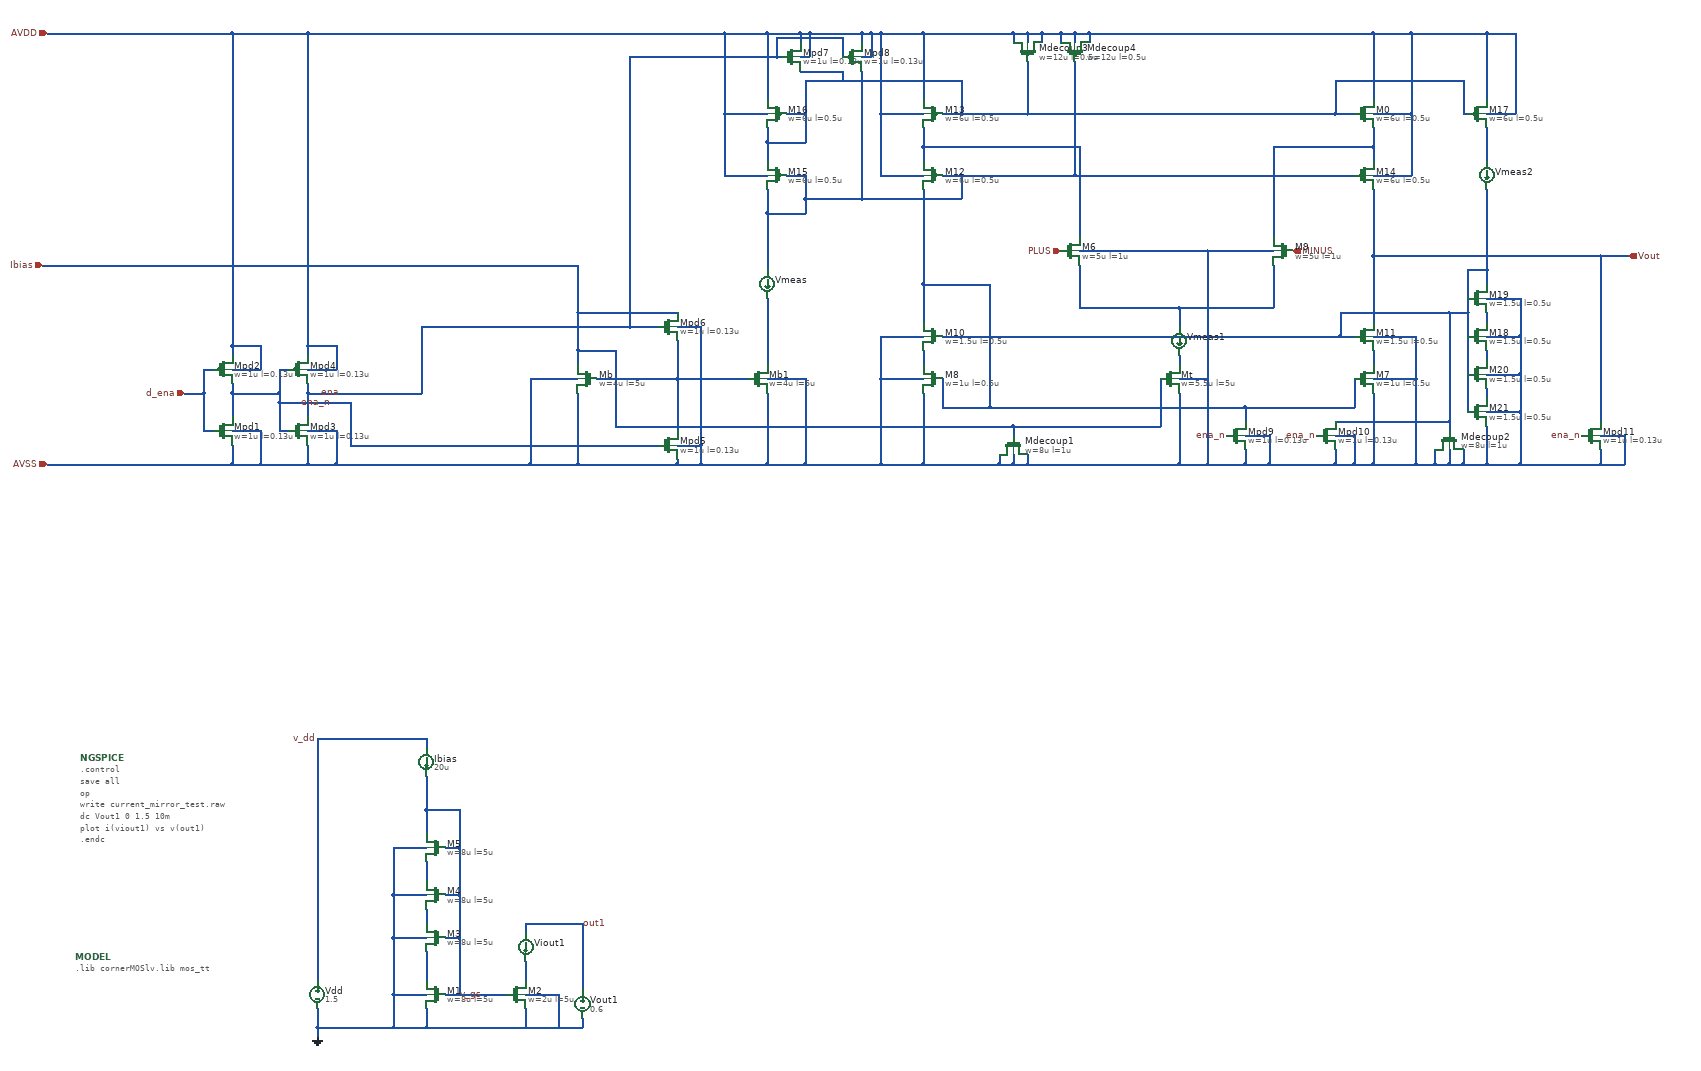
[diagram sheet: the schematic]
v {xschem version=3.4.6 file_version=1.2}
G {}
K {}
V {}
S {}
E {}
N 540 -170 540 -150 {
lab=GND}
N 700 -240 770 -240 {
lab=GND}
N 540 -780 770 -780 {
lab=v_dd}
N 810 -240 840 -240 {
lab=v_gs}
N 770 -780 770 -760 {
lab=v_dd}
N 770 -330 770 -270 {
lab=#net1}
N 980 -240 1050 -240 {
lab=GND}
N 540 -170 700 -170 {
lab=GND}
N 540 -210 540 -170 {
lab=GND}
N 700 -240 700 -170 {
lab=GND}
N 700 -170 770 -170 {
lab=GND}
N 770 -210 770 -170 {
lab=GND}
N 770 -170 980 -170 {
lab=GND}
N 980 -210 980 -170 {
lab=GND}
N 980 -170 1050 -170 {
lab=GND}
N 1050 -240 1050 -170 {
lab=GND}
N 1100 -190 1100 -170 {
lab=GND}
N 1050 -170 1100 -170 {
lab=GND}
N 840 -240 940 -240 {
lab=v_gs}
N 980 -390 1100 -390 {
lab=out1}
N 1100 -390 1100 -250 {
lab=out1}
N 980 -310 980 -270 {
lab=#net2}
N 980 -390 980 -370 {
lab=out1}
N 770 -630 770 -580 {lab=v_gs}
N 770 -520 770 -480 {lab=#net3}
N 770 -420 770 -390 {lab=#net4}
N 700 -360 700 -240 {lab=GND}
N 700 -550 770 -550 {lab=GND}
N 700 -450 770 -450 {lab=GND}
N 700 -550 700 -450 {lab=GND}
N 700 -360 770 -360 {lab=GND}
N 700 -450 700 -360 {lab=GND}
N 770 -630 840 -630 {lab=v_gs}
N 770 -700 770 -630 {lab=v_gs}
N 840 -360 840 -240 {lab=v_gs}
N 810 -360 840 -360 {lab=v_gs}
N 840 -450 840 -360 {lab=v_gs}
N 810 -450 840 -450 {lab=v_gs}
N 840 -550 840 -450 {lab=v_gs}
N 810 -550 840 -550 {lab=v_gs}
N 840 -630 840 -550 {lab=v_gs}
N 540 -780 540 -270 {lab=v_dd}
N 2150 -1780 2150 -1690 {lab=#net1}
N 2560 -1780 2560 -1690 {lab=#net1}
N 2360 -1690 2560 -1690 {lab=#net1}
N 2770 -1360 2860 -1360 {lab=AVSS}
N 2360 -1510 2360 -1360 {lab=AVSS}
N 2040 -1360 2360 -1360 {lab=AVSS}
N 2420 -1810 2560 -1810 {lab=AVSS}
N 2360 -1540 2420 -1540 {lab=AVSS}
N 2420 -1540 2420 -1360 {lab=AVSS}
N 2360 -1360 2420 -1360 {lab=AVSS}
N 2420 -1810 2420 -1540 {lab=AVSS}
N 2150 -1810 2420 -1810 {lab=AVSS}
N 1730 -1540 1820 -1540 {lab=AVSS}
N 1730 -1540 1730 -1360 {lab=AVSS}
N 2770 -1540 2860 -1540 {lab=AVSS}
N 2860 -1540 2860 -1360 {lab=AVSS}
N 2770 -1510 2770 -1360 {lab=AVSS}
N 2730 -1360 2770 -1360 {lab=AVSS}
N 1820 -1510 1820 -1360 {lab=AVSS}
N 1730 -1360 1820 -1360 {lab=AVSS}
N 1820 -1600 1820 -1570 {lab=#net2}
N 1730 -1630 1730 -1540 {lab=AVSS}
N 1730 -1630 1820 -1630 {lab=AVSS}
N 2770 -1600 2770 -1570 {lab=#net3}
N 1860 -1540 1860 -1480 {lab=#net4}
N 2730 -1540 2730 -1480 {lab=#net4}
N 1820 -1740 1820 -1660 {lab=#net4}
N 1820 -2030 1820 -2000 {lab=#net5}
N 2770 -2030 2770 -2000 {lab=#net6}
N 1820 -2270 1820 -2130 {lab=AVDD}
N 2170 -2270 2770 -2270 {lab=AVDD}
N 2770 -2270 2770 -2130 {lab=AVDD}
N 1730 -2100 1820 -2100 {lab=AVDD}
N 1730 -2270 1730 -2100 {lab=AVDD}
N 1730 -2270 1820 -2270 {lab=AVDD}
N 2770 -2100 2850 -2100 {lab=AVDD}
N 2850 -2270 2850 -2100 {lab=AVDD}
N 2770 -2270 2850 -2270 {lab=AVDD}
N 1730 -1970 1820 -1970 {lab=AVDD}
N 1730 -2100 1730 -1970 {lab=AVDD}
N 2770 -1970 2850 -1970 {lab=AVDD}
N 2850 -2100 2850 -1970 {lab=AVDD}
N 2770 -1800 2770 -1660 {lab=Vout}
N 2770 -1630 2860 -1630 {lab=AVSS}
N 2860 -1630 2860 -1540 {lab=AVSS}
N 2560 -2030 2560 -1840 {lab=#net6}
N 2560 -2030 2770 -2030 {lab=#net6}
N 2770 -2070 2770 -2030 {lab=#net6}
N 2150 -2030 2150 -1840 {lab=#net5}
N 1820 -2030 2150 -2030 {lab=#net5}
N 1820 -2070 1820 -2030 {lab=#net5}
N 1820 -1740 1960 -1740 {lab=#net4}
N 1820 -1940 1820 -1740 {lab=#net4}
N 1960 -1740 1960 -1480 {lab=#net4}
N 1860 -1480 1960 -1480 {lab=#net4}
N 2690 -2100 2730 -2100 {lab=#net7}
N 2140 -1970 2730 -1970 {lab=#net8}
N 2500 -1480 2730 -1480 {lab=#net4}
N 3250 -1800 3310 -1800 {lab=Vout}
N 2770 -1940 2770 -1800 {lab=Vout}
N 1090 -1600 1090 -1570 {lab=Ibias}
N 2320 -1540 2320 -1440 {lab=Ibias}
N 990 -1360 1090 -1360 {lab=AVSS}
N 2010 -1440 2320 -1440 {lab=Ibias}
N 1090 -1510 1090 -1360 {lab=AVSS}
N 990 -1540 1090 -1540 {lab=AVSS}
N 990 -1540 990 -1360 {lab=AVSS}
N 1090 -1600 1170 -1600 {lab=Ibias}
N 1090 -1680 1090 -1600 {lab=Ibias}
N 1170 -1600 1170 -1540 {lab=Ibias}
N 1130 -1540 1170 -1540 {lab=Ibias}
N 1170 -1540 1170 -1440 {lab=Ibias}
N 1490 -2040 1490 -2000 {lab=#net7}
N 1490 -2270 1490 -2130 {lab=AVDD}
N 1400 -2270 1490 -2270 {lab=AVDD}
N 1400 -1970 1490 -1970 {lab=AVDD}
N 1400 -2100 1400 -1970 {lab=AVDD}
N 1400 -2100 1490 -2100 {lab=AVDD}
N 1490 -2040 1570 -2040 {lab=#net7}
N 1490 -2070 1490 -2040 {lab=#net7}
N 1570 -2100 1570 -2040 {lab=#net7}
N 1530 -2100 1570 -2100 {lab=#net7}
N 1570 -1920 1570 -1890 {lab=#net8}
N 1530 -1970 1570 -1970 {lab=#net8}
N 1490 -1890 1570 -1890 {lab=#net8}
N 1490 -1940 1490 -1890 {lab=#net8}
N 1570 -1360 1730 -1360 {lab=AVSS}
N 2700 -1630 2730 -1630 {lab=#net9}
N 1900 -2170 1900 -2100 {lab=#net7}
N 1860 -2100 1900 -2100 {lab=#net7}
N 1900 -1970 1900 -1920 {lab=#net8}
N 1860 -1970 1900 -1970 {lab=#net8}
N 1710 -2270 1730 -2270 {lab=AVDD}
N 2690 -2170 2690 -2100 {lab=#net7}
N 2040 -2100 2690 -2100 {lab=#net7}
N 2690 -2170 2960 -2170 {lab=#net7}
N 2960 -2170 2960 -2100 {lab=#net7}
N 2960 -2100 2970 -2100 {lab=#net7}
N 3010 -2270 3010 -2130 {lab=AVDD}
N 2850 -2270 3010 -2270 {lab=AVDD}
N 3010 -2100 3070 -2100 {lab=AVDD}
N 3070 -2270 3070 -2100 {lab=AVDD}
N 3010 -2270 3070 -2270 {lab=AVDD}
N 3010 -1630 3080 -1630 {lab=AVSS}
N 3080 -1470 3080 -1360 {lab=AVSS}
N 3010 -1360 3080 -1360 {lab=AVSS}
N 2700 -1680 2700 -1630 {lab=#net9}
N 1860 -1630 2700 -1630 {lab=#net9}
N 1490 -1510 1490 -1360 {lab=AVSS}
N 1350 -1360 1490 -1360 {lab=AVSS}
N 1490 -1540 1570 -1540 {lab=AVSS}
N 1570 -1540 1570 -1360 {lab=AVSS}
N 1490 -1360 1570 -1360 {lab=AVSS}
N 1300 -1540 1450 -1540 {lab=Ibias}
N 2970 -1680 2970 -1470 {lab=#net9}
N 2930 -1680 2970 -1680 {lab=#net9}
N 1400 -2270 1400 -2100 {lab=AVDD}
N 1690 -1920 1900 -1920 {lab=#net8}
N 1570 -1970 1570 -1920 {lab=#net8}
N 1570 -2170 1570 -2100 {lab=#net7}
N 1650 -2170 1900 -2170 {lab=#net7}
N 1490 -1890 1490 -1770 {lab=#net8}
N 1490 -1710 1490 -1570 {lab=#net10}
N 2360 -1690 2360 -1650 {lab=#net1}
N 2150 -1690 2360 -1690 {lab=#net1}
N 2360 -1590 2360 -1570 {lab=#net11}
N 3010 -2070 3010 -2000 {lab=#net12}
N 3010 -1770 3010 -1740 {lab=#net9}
N 2010 -1440 2010 -1420 {lab=Ibias}
N 1170 -1440 2010 -1440 {lab=Ibias}
N 2010 -1380 2010 -1360 {lab=AVSS}
N 1980 -1360 2010 -1360 {lab=AVSS}
N 2040 -1380 2040 -1360 {lab=AVSS}
N 2010 -1360 2040 -1360 {lab=AVSS}
N 1980 -1380 1980 -1360 {lab=AVSS}
N 1820 -1360 1980 -1360 {lab=AVSS}
N 2930 -1450 2930 -1430 {lab=#net9}
N 2700 -1680 2930 -1680 {lab=#net9}
N 2960 -1390 2960 -1360 {lab=AVSS}
N 2930 -1360 2960 -1360 {lab=AVSS}
N 2930 -1390 2930 -1360 {lab=AVSS}
N 2900 -1360 2930 -1360 {lab=AVSS}
N 2900 -1390 2900 -1360 {lab=AVSS}
N 2860 -1360 2900 -1360 {lab=AVSS}
N 2010 -2270 2010 -2250 {lab=AVDD}
N 1820 -2270 2010 -2270 {lab=AVDD}
N 2040 -2270 2040 -2250 {lab=AVDD}
N 2010 -2270 2040 -2270 {lab=AVDD}
N 2070 -2270 2070 -2250 {lab=AVDD}
N 2040 -2270 2070 -2270 {lab=AVDD}
N 2110 -2270 2110 -2250 {lab=AVDD}
N 2070 -2270 2110 -2270 {lab=AVDD}
N 2140 -2270 2140 -2250 {lab=AVDD}
N 2110 -2270 2140 -2270 {lab=AVDD}
N 2170 -2270 2170 -2250 {lab=AVDD}
N 2140 -2270 2170 -2270 {lab=AVDD}
N 2040 -2210 2040 -2100 {lab=#net7}
N 1900 -2100 2040 -2100 {lab=#net7}
N 2140 -2210 2140 -1970 {lab=#net8}
N 1900 -1970 2140 -1970 {lab=#net8}
N 520 -1400 520 -1360 {
lab=AVSS}
N 460 -1430 480 -1430 {
lab=ena_n}
N 520 -1430 580 -1430 {
lab=AVSS}
N 580 -1430 580 -1360 {
lab=AVSS}
N 460 -1560 480 -1560 {
lab=ena_n}
N 520 -1610 520 -1590 {
lab=AVDD}
N 520 -1560 580 -1560 {
lab=AVDD}
N 580 -1610 580 -1560 {
lab=AVDD}
N 520 -1610 580 -1610 {
lab=AVDD}
N 520 -1510 520 -1460 {
lab=ena}
N 360 -1400 360 -1360 {
lab=AVSS}
N 300 -1430 320 -1430 {
lab=d_ena}
N 360 -1430 420 -1430 {
lab=AVSS}
N 420 -1430 420 -1360 {
lab=AVSS}
N 300 -1560 320 -1560 {
lab=d_ena}
N 360 -1610 360 -1590 {
lab=AVDD}
N 360 -1560 420 -1560 {
lab=AVDD}
N 420 -1610 420 -1560 {
lab=AVDD}
N 360 -1610 420 -1610 {
lab=AVDD}
N 260 -1510 300 -1510 {
lab=d_ena}
N 300 -1510 300 -1430 {
lab=d_ena}
N 360 -1510 460 -1510 {
lab=ena_n}
N 360 -1510 360 -1460 {
lab=ena_n}
N 360 -1530 360 -1510 {
lab=ena_n}
N 460 -1560 460 -1510 {
lab=ena_n}
N 300 -1560 300 -1510 {
lab=d_ena}
N 460 -1490 460 -1430 {
lab=ena_n}
N 520 -1510 760 -1510 {
lab=ena}
N 520 -1530 520 -1510 {
lab=ena}
N 580 -1360 990 -1360 {lab=AVSS}
N -30 -1360 360 -1360 {lab=AVSS}
N 360 -1360 420 -1360 {lab=AVSS}
N 420 -1360 520 -1360 {lab=AVSS}
N 520 -1360 580 -1360 {lab=AVSS}
N 520 -2270 1400 -2270 {lab=AVDD}
N 360 -2270 360 -1610 {lab=AVDD}
N -30 -2270 360 -2270 {lab=AVDD}
N 460 -1490 610 -1490 {lab=ena_n}
N 460 -1510 460 -1490 {
lab=ena_n}
N 520 -2270 520 -1610 {lab=AVDD}
N 360 -2270 520 -2270 {lab=AVDD}
N 1300 -1650 1350 -1650 {lab=AVSS}
N 1350 -1400 1350 -1360 {lab=AVSS}
N 1300 -1360 1350 -1360 {lab=AVSS}
N 1300 -1400 1350 -1400 {lab=AVSS}
N 1350 -1650 1350 -1400 {lab=AVSS}
N 1300 -1370 1300 -1360 {lab=AVSS}
N 1090 -1360 1300 -1360 {lab=AVSS}
N 610 -1490 610 -1400 {lab=ena_n}
N 610 -1400 1260 -1400 {lab=ena_n}
N 1300 -1540 1300 -1430 {lab=Ibias}
N 1170 -1540 1300 -1540 {lab=Ibias}
N 1090 -1680 1300 -1680 {lab=Ibias}
N 1090 -1780 1090 -1680 {lab=Ibias}
N 760 -1650 760 -1510 {lab=ena}
N 1200 -1650 1260 -1650 {lab=ena}
N 1300 -1620 1300 -1540 {lab=Ibias}
N 1200 -2220 1200 -1650 {lab=ena}
N 760 -1650 1200 -1650 {lab=ena}
N 1510 -2220 1520 -2220 {lab=ena}
N 1560 -2270 1560 -2250 {lab=AVDD}
N 1490 -2270 1560 -2270 {lab=AVDD}
N 1560 -2220 1580 -2220 {lab=AVDD}
N 1580 -2270 1580 -2220 {lab=AVDD}
N 1560 -2270 1580 -2270 {lab=AVDD}
N 1560 -2190 1650 -2190 {lab=#net7}
N 1650 -2190 1650 -2170 {lab=#net7}
N 1570 -2170 1650 -2170 {lab=#net7}
N 1690 -2190 1690 -1920 {lab=#net8}
N 1570 -1920 1690 -1920 {lab=#net8}
N 1690 -2270 1690 -2250 {lab=AVDD}
N 1580 -2270 1690 -2270 {lab=AVDD}
N 1690 -2220 1710 -2220 {lab=AVDD}
N 1710 -2270 1710 -2220 {lab=AVDD}
N 1690 -2270 1710 -2270 {lab=AVDD}
N 1650 -2260 1650 -2220 {lab=ena}
N 1510 -2260 1650 -2260 {lab=ena}
N 1510 -2260 1510 -2220 {lab=ena}
N 1200 -2220 1510 -2220 {lab=ena}
N 2500 -1420 2550 -1420 {lab=AVSS}
N 2550 -1420 2550 -1360 {lab=AVSS}
N 2500 -1360 2550 -1360 {lab=AVSS}
N 2500 -1390 2500 -1360 {lab=AVSS}
N 2420 -1360 2500 -1360 {lab=AVSS}
N 2690 -1390 2690 -1360 {lab=AVSS}
N 2550 -1360 2690 -1360 {lab=AVSS}
N 2690 -1420 2730 -1420 {lab=AVSS}
N 2730 -1420 2730 -1360 {lab=AVSS}
N 2690 -1360 2730 -1360 {lab=AVSS}
N 2500 -1480 2500 -1450 {lab=#net4}
N 1960 -1480 2500 -1480 {lab=#net4}
N 2690 -1450 2930 -1450 {lab=#net9}
N 2930 -1680 2930 -1450 {lab=#net9}
N 3250 -1800 3250 -1450 {lab=Vout}
N 2770 -1800 3250 -1800 {lab=Vout}
N 3250 -1390 3250 -1360 {lab=AVSS}
N 3080 -1360 3250 -1360 {lab=AVSS}
N 3250 -1420 3300 -1420 {lab=AVSS}
N 3300 -1420 3300 -1360 {lab=AVSS}
N 3250 -1360 3300 -1360 {lab=AVSS}
N -40 -1780 1090 -1780 {lab=Ibias}
N 3010 -1680 3010 -1660 {lab=#net13}
N 3010 -1600 3010 -1580 {lab=#net14}
N 3010 -1520 3010 -1500 {lab=#net15}
N 3010 -1440 3010 -1360 {lab=AVSS}
N 2960 -1360 3010 -1360 {lab=AVSS}
N 3010 -1710 3080 -1710 {lab=AVSS}
N 3080 -1710 3080 -1630 {lab=AVSS}
N 3010 -1550 3080 -1550 {lab=AVSS}
N 3080 -1630 3080 -1550 {lab=AVSS}
N 3010 -1470 3080 -1470 {lab=AVSS}
N 3080 -1550 3080 -1470 {lab=AVSS}
N 2970 -1770 2970 -1680 {lab=#net9}
N 2970 -1770 3010 -1770 {lab=#net9}
N 3010 -1940 3010 -1770 {lab=#net9}
C {devices/vsource.sym} 540 -240 0 0 {name=Vdd value=1.5}
C {devices/gnd.sym} 540 -150 0 0 {name=l3 lab=GND}
C {sg13g2_pr/sg13_lv_nmos.sym} 790 -240 0 1 {name=M1
l=5u
w=8u
ng=1
m=1
model=sg13_lv_nmos
spiceprefix=X
}
C {devices/isource.sym} 770 -730 0 0 {name=Ibias value=20u}
C {devices/lab_pin.sym} 840 -240 0 1 {name=p1 sig_type=std_logic lab=v_gs}
C {devices/lab_pin.sym} 540 -780 0 0 {name=p2 sig_type=std_logic lab=v_dd}
C {sg13g2_pr/sg13_lv_nmos.sym} 960 -240 0 0 {name=M2
l=5u
w=2u
ng=1
m=1
model=sg13_lv_nmos
spiceprefix=X
}
C {devices/vsource.sym} 1100 -220 0 0 {name=Vout1 value=0.6
}
C {devices/spice_probe.sym} 980 -390 0 0 {name=p3 attrs=""}
C {devices/spice_probe.sym} 840 -290 0 0 {name=p6 attrs=""}
C {devices/lab_pin.sym} 1100 -390 0 1 {name=p7 sig_type=std_logic lab=out1}
C {devices/ammeter.sym} 980 -340 0 0 {name=Viout1 savecurrent=true spice_ignore=0}
C {sg13g2_pr/sg13_lv_nmos.sym} 790 -360 0 1 {name=M3
l=5u
w=8u
ng=1
m=1
model=sg13_lv_nmos
spiceprefix=X
}
C {sg13g2_pr/sg13_lv_nmos.sym} 790 -450 0 1 {name=M4
l=5u
w=8u
ng=1
m=1
model=sg13_lv_nmos
spiceprefix=X
}
C {sg13g2_pr/sg13_lv_nmos.sym} 790 -550 0 1 {name=M5
l=5u
w=8u
ng=1
m=1
model=sg13_lv_nmos
spiceprefix=X
}
C {devices/code_shown.sym} 40 -740 0 0 {name=NGSPICE only_toplevel=true 
value="

.control
save all

op
write current_mirror_test.raw
dc Vout1 0 1.5 10m
plot i(viout1) vs v(out1)


.endc
"}
C {devices/code_shown.sym} 30 -320 0 0 {name=MODEL only_toplevel=true
format="tcleval( @value )"
value=".lib cornerMOSlv.lib mos_tt
"}
C {devices/title.sym} 190 80 0 0 {name=l5 author="(c) 2025 Thesis_HP, Apache-2.0 license"}
C {ipin.sym} 2110 -1810 0 0 {name=p4 lab=PLUS}
C {ipin.sym} 2600 -1810 0 1 {name=p5 lab=MINUS
}
C {opin.sym} 3310 -1800 0 0 {name=p8 lab=Vout}
C {ipin.sym} -30 -2270 0 0 {name=p9 lab=AVDD}
C {sg13g2_pr/sg13_lv_nmos.sym} 2130 -1810 0 0 {name=M6
l=1u
w=5u
ng=1
m=1
model=sg13_lv_nmos
spiceprefix=X
}
C {sg13g2_pr/sg13_lv_nmos.sym} 2340 -1540 0 0 {name=Mt
l=5u
w=5.5u
ng=3
m=1
model=sg13_lv_nmos
spiceprefix=X
}
C {ipin.sym} -30 -1360 0 0 {name=p10 lab=AVSS}
C {sg13g2_pr/sg13_lv_nmos.sym} 2750 -1540 0 0 {name=M7
l=0.5u
w=1u
ng=1
m=1
model=sg13_lv_nmos
spiceprefix=X
}
C {sg13g2_pr/sg13_lv_nmos.sym} 1840 -1540 0 1 {name=M8
l=0.5u
w=1u
ng=1
m=1
model=sg13_lv_nmos
spiceprefix=X
}
C {sg13g2_pr/sg13_lv_nmos.sym} 2580 -1810 0 1 {name=M9
l=1u
w=5u
ng=1
m=1
model=sg13_lv_nmos
spiceprefix=X
}
C {sg13g2_pr/sg13_lv_nmos.sym} 1840 -1630 0 1 {name=M10
l=0.5u
w=1.5u
ng=1
m=1
model=sg13_lv_nmos
spiceprefix=X
}
C {sg13g2_pr/sg13_lv_nmos.sym} 2750 -1630 0 0 {name=M11
l=0.5u
w=1.5u
ng=1
m=1
model=sg13_lv_nmos
spiceprefix=X
}
C {sg13g2_pr/sg13_lv_pmos.sym} 1840 -1970 0 1 {name=M12
l=0.5u
w=6u
ng=1
m=1
model=sg13_lv_pmos
spiceprefix=X
}
C {sg13g2_pr/sg13_lv_pmos.sym} 1840 -2100 0 1 {name=M13
l=0.5u
w=6u
ng=1
m=1
model=sg13_lv_pmos
spiceprefix=X
}
C {sg13g2_pr/sg13_lv_pmos.sym} 2750 -1970 0 0 {name=M14
l=0.5u
w=6u
ng=1
m=1
model=sg13_lv_pmos
spiceprefix=X
}
C {sg13g2_pr/sg13_lv_pmos.sym} 2750 -2100 0 0 {name=M0
l=0.5u
w=6u
ng=1
m=1
model=sg13_lv_pmos
spiceprefix=X
}
C {ipin.sym} -40 -1780 0 0 {name=p11 lab=Ibias
}
C {sg13g2_pr/sg13_lv_nmos.sym} 1110 -1540 0 1 {name=Mb
l=5u
w=4u
ng=2
m=1
model=sg13_lv_nmos
spiceprefix=X
}
C {sg13g2_pr/sg13_lv_pmos.sym} 1510 -1970 0 1 {name=M15
l=0.5u
w=6u
ng=2
m=1
model=sg13_lv_pmos
spiceprefix=X
}
C {sg13g2_pr/sg13_lv_pmos.sym} 1510 -2100 0 1 {name=M16
l=0.5u
w=6u
ng=2
m=1
model=sg13_lv_pmos
spiceprefix=X
}
C {sg13g2_pr/sg13_lv_pmos.sym} 2990 -2100 0 0 {name=M17
l=0.5u
w=6u
ng=2
m=1
model=sg13_lv_pmos
spiceprefix=X
}
C {sg13g2_pr/sg13_lv_nmos.sym} 2990 -1630 0 0 {name=M18
l=0.5u
w=1.5u
ng=1
m=1
model=sg13_lv_nmos
spiceprefix=X
}
C {sg13g2_pr/sg13_lv_nmos.sym} 1470 -1540 0 0 {name=Mb1
l=5u
w=4u
ng=2
m=1
model=sg13_lv_nmos
spiceprefix=X
}
C {devices/title.sym} 1500 -1230 0 0 {name=l1 author="(c) 2025 Thesis_HP, Apache-2.0 license"}
C {devices/ammeter.sym} 1490 -1740 0 1 {name=Vmeas savecurrent=true spice_ignore=0}
C {devices/ammeter.sym} 2360 -1620 0 1 {name=Vmeas1 savecurrent=true spice_ignore=0}
C {devices/ammeter.sym} 3010 -1970 0 1 {name=Vmeas2 savecurrent=true spice_ignore=0}
C {sg13g2_pr/sg13_lv_nmos.sym} 2010 -1400 3 1 {name=Mdecoup1
l=1u
w=8u
ng=4
m=1
model=sg13_lv_nmos
spiceprefix=X
}
C {sg13g2_pr/sg13_lv_nmos.sym} 2930 -1410 3 1 {name=Mdecoup2
l=1u
w=8u
ng=4
m=1
model=sg13_lv_nmos
spiceprefix=X
}
C {sg13g2_pr/sg13_lv_pmos.sym} 2040 -2230 1 1 {name=Mdecoup3
l=0.5u
w=12u
ng=4
m=1
model=sg13_lv_pmos
spiceprefix=X
}
C {sg13g2_pr/sg13_lv_pmos.sym} 2140 -2230 1 1 {name=Mdecoup4
l=0.5u
w=12u
ng=4
m=1
model=sg13_lv_pmos
spiceprefix=X
}
C {sg13g2_pr/sg13_lv_nmos.sym} 500 -1430 0 0 {name=Mpd3
l=0.13u
w=1u
ng=1
m=1
model=sg13_lv_nmos
spiceprefix=X
}
C {sg13g2_pr/sg13_lv_pmos.sym} 500 -1560 0 0 {name=Mpd4
l=0.13u
w=1u
ng=1
m=1
model=sg13_lv_pmos
spiceprefix=X
}
C {devices/ipin.sym} 260 -1510 0 0 {name=p12 lab=d_ena}
C {devices/lab_wire.sym} 570 -1490 0 0 {name=p13 sig_type=std_logic lab=ena_n}
C {sg13g2_pr/sg13_lv_nmos.sym} 340 -1430 0 0 {name=Mpd1
l=0.13u
w=1u
ng=1
m=1
model=sg13_lv_nmos
spiceprefix=X}
C {sg13g2_pr/sg13_lv_pmos.sym} 340 -1560 0 0 {name=Mpd2
l=0.13u
w=1u
ng=1
m=1
model=sg13_lv_pmos
spiceprefix=X
}
C {devices/lab_wire.sym} 590 -1510 0 0 {name=p15 sig_type=std_logic lab=ena}
C {sg13g2_pr/sg13_lv_nmos.sym} 1280 -1400 0 0 {name=Mpd5
l=0.13u
w=1u
ng=1
m=1
model=sg13_lv_nmos
spiceprefix=X
}
C {sg13g2_pr/sg13_lv_nmos.sym} 1280 -1650 0 0 {name=Mpd6
l=0.13u
w=1u
ng=1
m=1
model=sg13_lv_nmos
spiceprefix=X
}
C {sg13g2_pr/sg13_lv_pmos.sym} 1540 -2220 0 0 {name=Mpd7
l=0.13u
w=1u
ng=1
m=1
model=sg13_lv_pmos
spiceprefix=X
}
C {sg13g2_pr/sg13_lv_pmos.sym} 1670 -2220 0 0 {name=Mpd8
l=0.13u
w=1u
ng=1
m=1
model=sg13_lv_pmos
spiceprefix=X
}
C {sg13g2_pr/sg13_lv_nmos.sym} 2480 -1420 0 0 {name=Mpd9
l=0.13u
w=1u
ng=1
m=1
model=sg13_lv_nmos
spiceprefix=X
}
C {sg13g2_pr/sg13_lv_nmos.sym} 2670 -1420 0 0 {name=Mpd10
l=0.13u
w=1u
ng=1
m=1
model=sg13_lv_nmos
spiceprefix=X
}
C {devices/lab_wire.sym} 2460 -1420 0 0 {name=p14 sig_type=std_logic lab=ena_n}
C {devices/lab_wire.sym} 2650 -1420 0 0 {name=p16 sig_type=std_logic lab=ena_n}
C {sg13g2_pr/sg13_lv_nmos.sym} 3230 -1420 0 0 {name=Mpd11
l=0.13u
w=1u
ng=1
m=1
model=sg13_lv_nmos
spiceprefix=X
}
C {devices/lab_wire.sym} 3210 -1420 0 0 {name=p17 sig_type=std_logic lab=ena_n}
C {sg13g2_pr/sg13_lv_nmos.sym} 2990 -1710 0 0 {name=M19
l=0.5u
w=1.5u
ng=1
m=1
model=sg13_lv_nmos
spiceprefix=X
}
C {sg13g2_pr/sg13_lv_nmos.sym} 2990 -1550 0 0 {name=M20
l=0.5u
w=1.5u
ng=1
m=1
model=sg13_lv_nmos
spiceprefix=X
}
C {sg13g2_pr/sg13_lv_nmos.sym} 2990 -1470 0 0 {name=M21
l=0.5u
w=1.5u
ng=1
m=1
model=sg13_lv_nmos
spiceprefix=X
}
